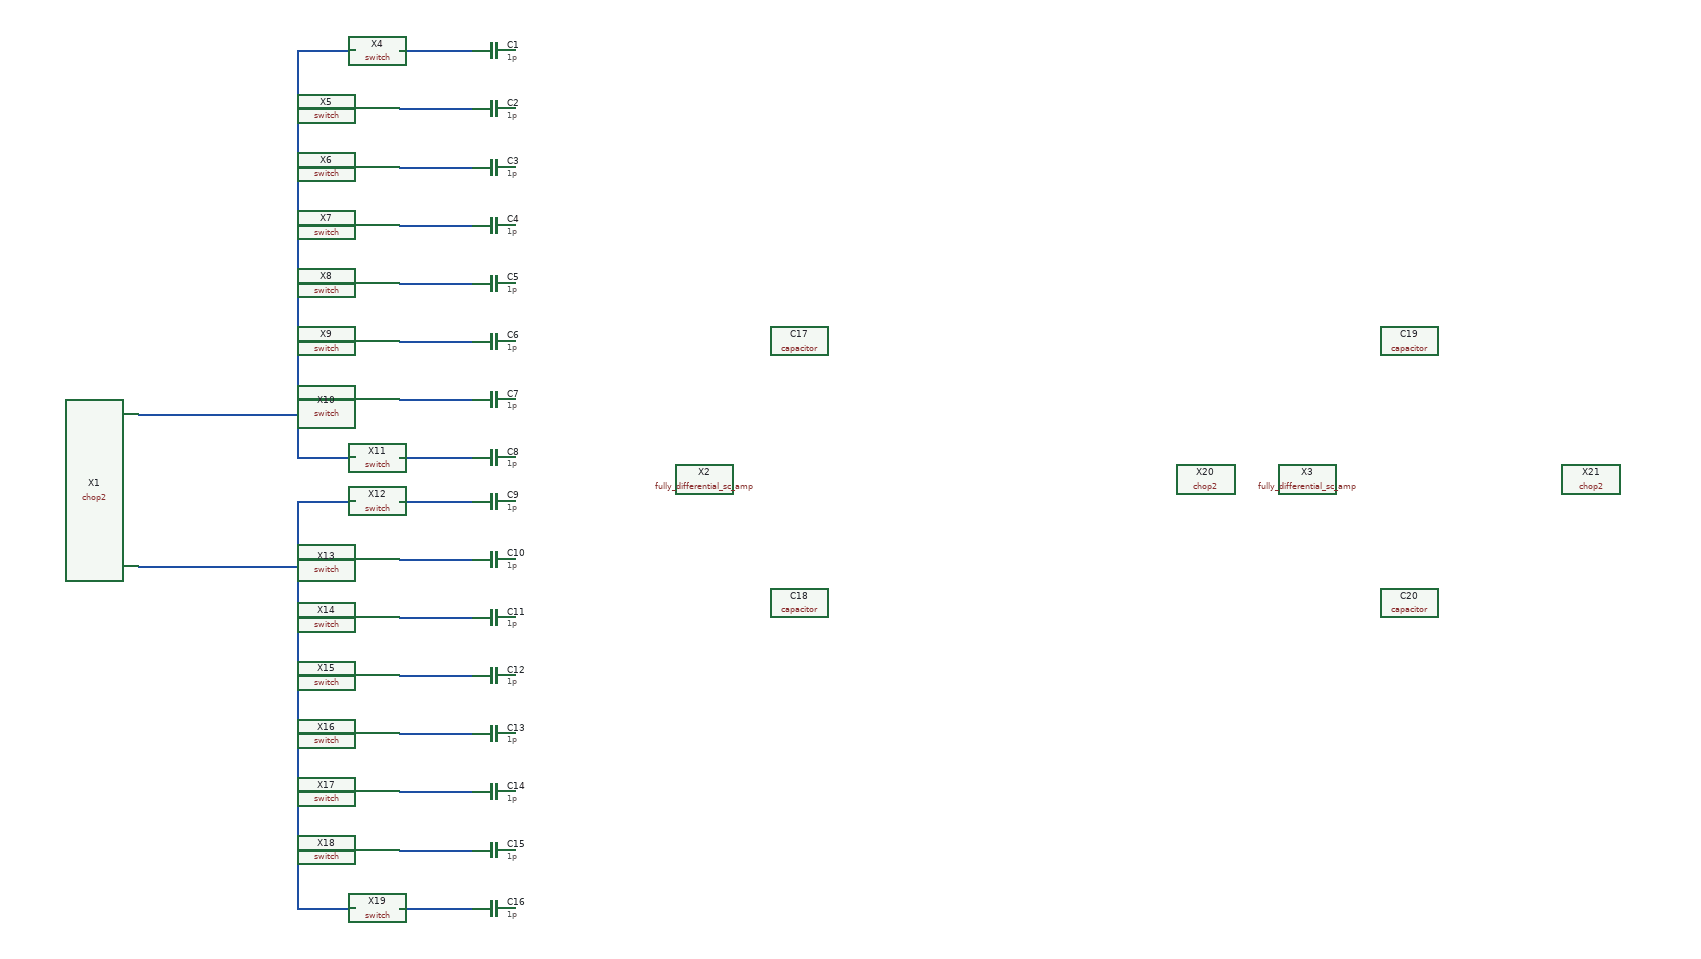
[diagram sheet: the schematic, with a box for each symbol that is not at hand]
v {xschem version=2.9.9 file_version=1.2 }
G {}
K {}
V {}
S {}
E {}
N 280 -680 500 -680 { lab=#net1}
N 500 -620 580 -620 { lab=#net1}
N 500 -1180 500 -620 { lab=#net1}
N 500 -1180 580 -1180 { lab=#net1}
N 500 -1100 580 -1100 { lab=#net1}
N 500 -1020 580 -1020 { lab=#net1}
N 500 -940 580 -940 { lab=#net1}
N 500 -860 580 -860 { lab=#net1}
N 500 -780 580 -780 { lab=#net1}
N 500 -700 580 -700 { lab=#net1}
N 500 0 580 0 { lab=#net2}
N 500 -560 500 0 { lab=#net2}
N 500 -560 580 -560 { lab=#net2}
N 500 -480 580 -480 { lab=#net2}
N 500 -400 580 -400 { lab=#net2}
N 500 -320 580 -320 { lab=#net2}
N 500 -240 580 -240 { lab=#net2}
N 500 -160 580 -160 { lab=#net2}
N 500 -80 580 -80 { lab=#net2}
N 280 -470 500 -470 { lab=#net2}
N 640 -0 740 0 { lab=#net3}
N 640 -80 740 -80 { lab=#net4}
N 640 -160 740 -160 { lab=#net5}
N 640 -240 740 -240 { lab=#net6}
N 640 -320 740 -320 { lab=#net7}
N 640 -400 740 -400 { lab=#net8}
N 640 -480 740 -480 { lab=#net9}
N 640 -560 740 -560 { lab=#net10}
N 640 -620 740 -620 { lab=#net11}
N 640 -700 740 -700 { lab=#net12}
N 640 -780 740 -780 { lab=#net13}
N 640 -860 740 -860 { lab=#net14}
N 640 -940 740 -940 { lab=#net15}
N 640 -1020 740 -1020 { lab=#net16}
N 640 -1100 740 -1100 { lab=#net17}
N 640 -1180 740 -1180 { lab=#net18}
C {/home/madvlsi/Documents/MADVLSI-Final_Project/schematic/chop2.sym} 180 -580 0 0 {name=X1 Wp=1 Lp=0.15 WW=1 LL=0.15}
C {/home/madvlsi/Documents/MADVLSI-Final_Project/schematic/fully_differential_sc_amp.sym} 1060 -590 0 0 {name=X2}
C {/home/madvlsi/Documents/MADVLSI-Final_Project/schematic/fully_differential_sc_amp.sym} 1890 -590 0 0 {name=X3}
C {madvlsi/capacitor.sym} 770 -1180 1 0 {name=C1
value=1p
m=1}
C {madvlsi/capacitor.sym} 770 -1100 1 0 {name=C2
value=1p
m=1}
C {madvlsi/capacitor.sym} 770 -1020 1 0 {name=C3
value=1p
m=1}
C {madvlsi/capacitor.sym} 770 -940 1 0 {name=C4
value=1p
m=1}
C {madvlsi/capacitor.sym} 770 -860 1 0 {name=C5
value=1p
m=1}
C {madvlsi/capacitor.sym} 770 -780 1 0 {name=C6
value=1p
m=1}
C {madvlsi/capacitor.sym} 770 -700 1 0 {name=C7
value=1p
m=1}
C {madvlsi/capacitor.sym} 770 -620 1 0 {name=C8
value=1p
m=1}
C {madvlsi/capacitor.sym} 770 -560 1 0 {name=C9
value=1p
m=1}
C {madvlsi/capacitor.sym} 770 -480 1 0 {name=C10
value=1p
m=1}
C {madvlsi/capacitor.sym} 770 -400 1 0 {name=C11
value=1p
m=1}
C {madvlsi/capacitor.sym} 770 -320 1 0 {name=C12
value=1p
m=1}
C {madvlsi/capacitor.sym} 770 -240 1 0 {name=C13
value=1p
m=1}
C {madvlsi/capacitor.sym} 770 -160 1 0 {name=C14
value=1p
m=1}
C {madvlsi/capacitor.sym} 770 -80 1 0 {name=C15
value=1p
m=1}
C {madvlsi/capacitor.sym} 770 0 1 0 {name=C16
value=1p
m=1}
C {/home/madvlsi/Documents/MADVLSI-Final_Project/schematic/switch.sym} 610 -1180 0 0 {name=X4 Wp=1 Lp=0.15 WW=1 LL=0.15}
C {/home/madvlsi/Documents/MADVLSI-Final_Project/schematic/switch.sym} 610 -1100 0 0 {name=X5 Wp=1 Lp=0.15 WW=1 LL=0.15}
C {/home/madvlsi/Documents/MADVLSI-Final_Project/schematic/switch.sym} 610 -1020 0 0 {name=X6 Wp=1 Lp=0.15 WW=1 LL=0.15}
C {/home/madvlsi/Documents/MADVLSI-Final_Project/schematic/switch.sym} 610 -940 0 0 {name=X7 Wp=1 Lp=0.15 WW=1 LL=0.15}
C {/home/madvlsi/Documents/MADVLSI-Final_Project/schematic/switch.sym} 610 -860 0 0 {name=X8 Wp=1 Lp=0.15 WW=1 LL=0.15}
C {/home/madvlsi/Documents/MADVLSI-Final_Project/schematic/switch.sym} 610 -780 0 0 {name=X9 Wp=1 Lp=0.15 WW=1 LL=0.15}
C {/home/madvlsi/Documents/MADVLSI-Final_Project/schematic/switch.sym} 610 -700 0 0 {name=X10 Wp=1 Lp=0.15 WW=1 LL=0.15}
C {/home/madvlsi/Documents/MADVLSI-Final_Project/schematic/switch.sym} 610 -620 0 0 {name=X11 Wp=1 Lp=0.15 WW=1 LL=0.15}
C {/home/madvlsi/Documents/MADVLSI-Final_Project/schematic/switch.sym} 610 -560 0 0 {name=X12 Wp=1 Lp=0.15 WW=1 LL=0.15}
C {/home/madvlsi/Documents/MADVLSI-Final_Project/schematic/switch.sym} 610 -480 0 0 {name=X13 Wp=1 Lp=0.15 WW=1 LL=0.15}
C {/home/madvlsi/Documents/MADVLSI-Final_Project/schematic/switch.sym} 610 -400 0 0 {name=X14 Wp=1 Lp=0.15 WW=1 LL=0.15}
C {/home/madvlsi/Documents/MADVLSI-Final_Project/schematic/switch.sym} 610 -320 0 0 {name=X15 Wp=1 Lp=0.15 WW=1 LL=0.15}
C {/home/madvlsi/Documents/MADVLSI-Final_Project/schematic/switch.sym} 610 -240 0 0 {name=X16 Wp=1 Lp=0.15 WW=1 LL=0.15}
C {/home/madvlsi/Documents/MADVLSI-Final_Project/schematic/switch.sym} 610 -160 0 0 {name=X17 Wp=1 Lp=0.15 WW=1 LL=0.15}
C {/home/madvlsi/Documents/MADVLSI-Final_Project/schematic/switch.sym} 610 -80 0 0 {name=X18 Wp=1 Lp=0.15 WW=1 LL=0.15}
C {/home/madvlsi/Documents/MADVLSI-Final_Project/schematic/switch.sym} 610 0 0 0 {name=X19 Wp=1 Lp=0.15 WW=1 LL=0.15}
C {madvlsi/capacitor.sym} 1190 -780 1 0 {name=C17
value=1p
m=1}
C {madvlsi/capacitor.sym} 1190 -420 1 0 {name=C18
value=1p
m=1}
C {madvlsi/capacitor.sym} 2030 -780 1 0 {name=C19
value=1p
m=1}
C {madvlsi/capacitor.sym} 2030 -420 1 0 {name=C20
value=1p
m=1}
C {/home/madvlsi/Documents/MADVLSI-Final_Project/schematic/chop2.sym} 1750 -590 0 0 {name=X20 Wp=1 Lp=0.15 WW=1 LL=0.15}
C {/home/madvlsi/Documents/MADVLSI-Final_Project/schematic/chop2.sym} 2280 -590 0 0 {name=X21 Wp=1 Lp=0.15 WW=1 LL=0.15}
